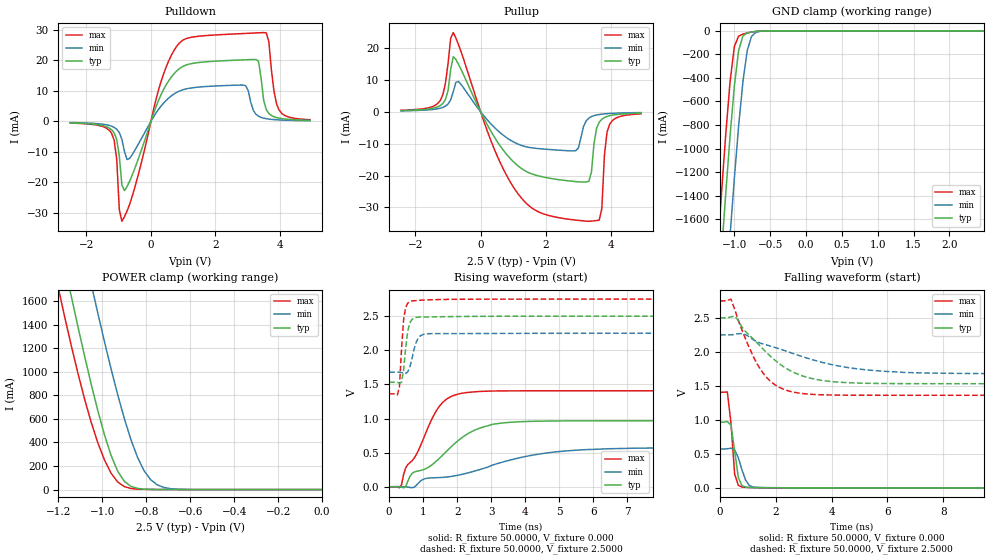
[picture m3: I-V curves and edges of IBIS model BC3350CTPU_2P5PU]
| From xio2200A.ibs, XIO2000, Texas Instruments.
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|   Model BC3350CTPU_2P5PU
[Model]   BC3350CTPU_2P5PU
Model_type   I/O
Polarity   Non-Inverting
Enable   Active-Low
Vinl =   0.7500V
Vinh =   1.7500V
Vmeas =   1.2500V
Cref =  15.0000pF
Rref = 100.0000M
Vref =  0.000V
C_comp   1.5218pF   1.5459pF   1.5123pF
[Temperature Range]   25.0000   0.1250k   -40.0000
[Voltage Range]   2.5000V   2.2500V   2.7500V
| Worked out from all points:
|   slope of the pulldown table from 0 to 0.375 V, typ, clamps not added: 37.2 ohm
|   slope of the pullup table from 0 to 0.375 V, typ, clamps not added: 52.5 ohm
|   GND clamp passes 1 mA (typ) near -0.59 V on its own axis
|   POWER clamp passes 1 mA (typ) near -0.75 V on its own axis
|   rising waveform, R_fixture 50.0000, V_fixture 0.000: 20-80 % time 1.63ns typ, 3.12ns min, 911ps max; typ from 0 V to 0.967 V
|   rising waveform, R_fixture 50.0000, V_fixture 2.5000: 20-80 % time 132ps typ, 185ps min, 110ps max; typ from 1.53 V to 2.5 V
|   falling waveform, R_fixture 50.0000, V_fixture 0.000: 20-80 % time 197ps typ, 276ps min, 166ps max; typ from 0.967 V to 0 V
|   falling waveform, R_fixture 50.0000, V_fixture 2.5000: 20-80 % time 1.61ns typ, 2.84ns min, 994ps max; typ from 2.5 V to 1.53 V
[Pulldown]
| voltage   I(typ)   I(min)   I(max)
-2.5V     -467uA     -355uA     -521uA
-1.22V    -2.719mA   -1.548mA   -3.89mA
-1.06V    -5.93mA    -2.554mA   -12.42mA
-900mV    -20.83mA   -5.841mA   -32.72mA
-660mV    -19.6mA    -12.09mA   -27.16mA
380mV     10.17mA    5.837mA    15.14mA
1.02V     18.17mA    10.47mA    26.8mA
2.94V     20.21mA    11.72mA    28.84mA
3.26V     20.3mA     2.359mA    29mA
3.58V     3.907mA    903.9uA    29.01mA
3.98V     1.074mA    495.1uA    3.709mA
4.94V     373uA      234uA      572uA
[Pullup]
| voltage   I(typ)   I(min)   I(max)
-2.44V    386uA      291uA      479uA
-1.24V    1.945mA    1.132mA    3.544mA
-840mV    17.3mA     6.311mA    24.85mA
-680mV    14.89mA    9.474mA    21.07mA
1.08V     -16.37mA   -9.818mA   -24.74mA
2.92V     -21.89mA   -12.18mA   -33.96mA
3.32V     -21.82mA   -1.989mA   -34.34mA
3.56V     -5.145mA   -999.9uA   -34.1mA
3.72V     -2.328mA   -742.1uA   -30.34mA
3.8V      -1.8mA     -656.3uA   -13.54mA
3.96V     -1.227mA   -532.1uA   -3.918mA
4.92V     -412uA     -247uA     -636uA
[GND_clamp]
| voltage   I(typ)   I(min)   I(max)
-2.5V     -14.57A    -15.39A    -14.11A
-1.24V    -2.437A    -3.32A     -1.92A
-1.18V    -1.901A    -2.781A    -1.388A
-1.12V    -1.385A    -2.254A    -883mA
-1.06V    -898.7mA   -1.743A    -437mA
-1V       -472.1mA   -1.256A    -134.5mA
-940mV    -167.3mA   -809.4mA   -44.68mA
-880mV    -43.65mA   -430.8mA   -28.16mA
-820mV    -17.66mA   -168mA     -18.71mA
-760mV    -9.862mA   -47.59mA   -10.99mA
-700mV    -5.196mA   -13.22mA   -5.204mA
2.48V     104.5pA    201.3nA    85.44pA
[POWER_clamp]
| voltage   I(typ)   I(min)   I(max)
-2.49V    14.56A     15.39A     14.09A
-1.2V     2.157A     3.049A     1.709A
-1.14V    1.631A     2.515A     1.213A
-1.05V    891mA      1.742A     568.1mA
-1.02V    667.6mA    1.494A     395.8mA
-960mV    290.1mA    1.024A     139.6mA
-930mV    156.3mA    806.1mA    65.19mA
-900mV    70.81mA    604.8mA    26.03mA
-840mV    10.16mA    275.4mA    3.647mA
-780mV    1.777mA    84.15mA    1.23mA
-660mV    345.8uA    3.568mA    382.4uA
0V        107.3pA    2.193nA    101.5pA
[Ramp]
| variable   typ   min   max
dV/dt_r   0.5801/1.6072n   0.3429/3.1475n   0.8439/0.8921n
dV/dt_f   0.5811/1.5919n   0.3426/2.8083n   0.8330/0.9837n
R_load = 50.0000
[Rising Waveform]
R_fixture = 50.0000
V_fixture = 0.000
V_fixture_min = 0.000
V_fixture_max = 0.000
| time   V(typ)   V(min)   V(max)
0s        1.141nV    28.31nV    608.5pV
303ps     1.167mV    773.8uV    -16.01mV
484.8ps   1.286mV    -687.1uV   275.1mV
666.7ps   190.5mV    -14.02mV   377.3mV
1.394ns   378.1mV    132.9mV    1.117V
2ns       664.1mV    166.2mV    1.354V
2.667ns   858.8mV    252.3mV    1.396V
3.636ns   946.8mV    401mV      1.405V
5.879ns   966.2mV    545.9mV    1.406V
11.16ns   966.9mV    571.4mV    1.407V
[Rising Waveform]
R_fixture = 50.0000
V_fixture = 2.5000
V_fixture_min = 2.2500
V_fixture_max = 2.7500
| time   V(typ)   V(min)   V(max)
0s        1.532V     1.679V     1.362V
242.4ps   1.53V      1.68V      1.346V
303ps     1.514V     1.679V     1.465V
363.6ps   1.533V     1.673V     2.014V
424.2ps   1.703V     1.664V     2.448V
545.5ps   2.277V     1.684V     2.69V
666.7ps   2.45V      1.868V     2.723V
848.5ps   2.486V     2.174V     2.732V
1.091ns   2.488V     2.24V      2.738V
9.455ns   2.5V       2.25V      2.75V
[Falling Waveform]
R_fixture = 50.0000
V_fixture = 0.000
V_fixture_min = 0.000
V_fixture_max = 0.000
| time   V(typ)   V(min)   V(max)
0s        966.9mV    571.5mV    1.407V
262.6ps   976.8mV    574mV      1.411V
393.9ps   921.3mV    584.2mV    953.5mV
525.3ps   545.8mV    557.5mV    199.6mV
656.6ps   150.4mV    444mV      36.9mV
787.9ps   33.05mV    265.5mV    11.91mV
919.2ps   11.07mV    112.7mV    7.004mV
1.051ns   6.645mV    35.12mV    5.089mV
1.313ns   4.07mV     5.807mV    2.944mV
13ns      403.6nV    1.121uV    308.5nV
[Falling Waveform]
R_fixture = 50.0000
V_fixture = 2.5000
V_fixture_min = 2.2500
V_fixture_max = 2.7500
| time   V(typ)   V(min)   V(max)
0s        2.5V       2.25V      2.75V
393.9ps   2.515V     2.25V      2.776V
525.3ps   2.525V     2.257V     2.628V
1.051ns   2.245V     2.221V     2.059V
1.576ns   2.029V     2.113V     1.671V
1.97ns    1.877V     2.065V     1.516V
2.495ns   1.728V     1.994V     1.421V
3.677ns   1.579V     1.844V     1.368V
5.647ns   1.536V     1.721V     1.362V
13ns      1.532V     1.679V     1.362V
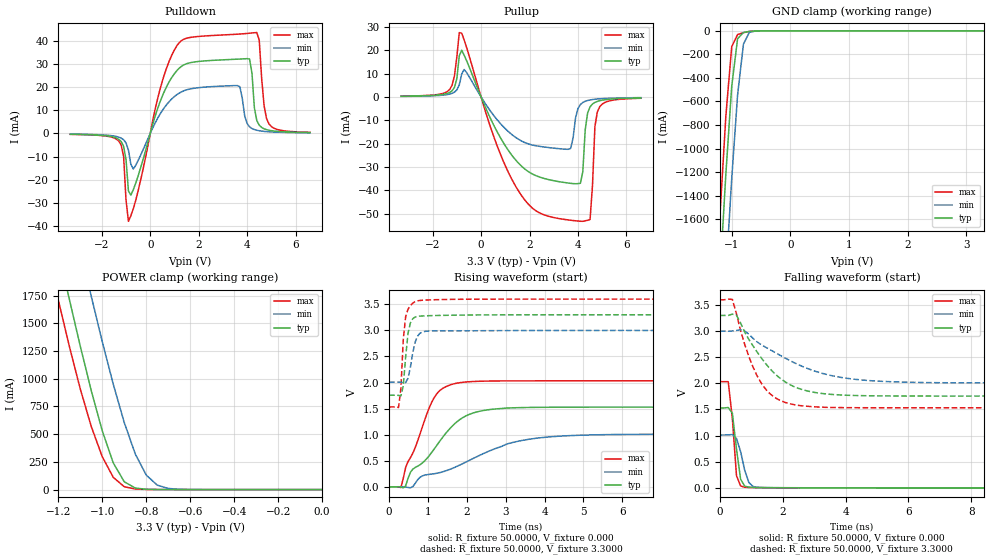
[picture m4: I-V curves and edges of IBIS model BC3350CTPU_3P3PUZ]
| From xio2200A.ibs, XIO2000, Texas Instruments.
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|   Model BC3350CTPU_3P3PUZ
[Model]   BC3350CTPU_3P3PUZ
Model_type   I/O
Polarity   Non-Inverting
Enable   Active-Low
Vinl =   0.9900V
Vinh =   2.3100V
Vmeas =   1.6500V
Cref =  15.0000pF
Rref = 100.0000M
Vref =  0.000V
C_comp   1.9215pF   2.0161pF   1.9194pF
[Temperature Range]   25.0000   0.1250k   -40.0000
[Voltage Range]   3.3000V   3.0000V   3.6000V
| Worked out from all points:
|   slope of the pulldown table from 0 to 0.495 V, typ, clamps not added: 30.8 ohm
|   slope of the pullup table from 0 to 0.495 V, typ, clamps not added: 43 ohm
|   GND clamp passes 1 mA (typ) near -0.59 V on its own axis
|   POWER clamp passes 1 mA (typ) near -0.75 V on its own axis
|   rising waveform, R_fixture 50.0000, V_fixture 0.000: 20-80 % time 1.13ns typ, 2.15ns min, 655ps max; typ from 0 V to 1.53 V
|   rising waveform, R_fixture 50.0000, V_fixture 3.3000: 20-80 % time 123ps typ, 161ps min, 108ps max; typ from 1.76 V to 3.3 V
|   falling waveform, R_fixture 50.0000, V_fixture 0.000: 20-80 % time 191ps typ, 267ps min, 167ps max; typ from 1.53 V to 0 V
|   falling waveform, R_fixture 50.0000, V_fixture 3.3000: 20-80 % time 1.21ns typ, 2.01ns min, 801ps max; typ from 3.3 V to 1.76 V
[Pulldown]
| voltage   I(typ)   I(min)   I(max)
-3.3V     -368uA     -295uA     -396uA
-1.3V     -2.536mA   -1.588mA   -3.308mA
-1.1V     -5.574mA   -2.722mA   -9.851mA
-900mV    -24.93mA   -7.21mA    -38.07mA
-700mV    -24.39mA   -15.39mA   -32.64mA
400mV     13.55mA    8.28mA     19mA
1.1V      27.23mA    16.82mA    38.01mA
3.6V      32.19mA    20.74mA    43.02mA
4.1V      32.24mA    2.869mA    43.43mA
4.4V      5.593mA    1.375mA    43.71mA
4.9V      1.396mA    719.1uA    4.161mA
6.6V      373uA      269uA      490uA
[Pullup]
| voltage   I(typ)   I(min)   I(max)
-3.3V     287uA      231uA      331uA
-1.3V     1.913mA    1.209mA    3.156mA
-800mV    19.97mA    9.765mA    27.29mA
600mV     -13.66mA   -8.958mA   -19.14mA
1.6V      -28.91mA   -18.45mA   -41.12mA
3.7V      -36.98mA   -22mA      -52.77mA
4.2V      -32.06mA   -2.382mA   -53.22mA
4.3V      -14.02mA   -1.866mA   -53mA
4.5V      -4.233mA   -1.292mA   -52.47mA
4.7V      -2.35mA    -983uA     -12.62mA
4.9V      -1.61mA    -791.8uA   -4.169mA
6.6V      -427uA     -295uA     -564uA
[GND_clamp]
| voltage   I(typ)   I(min)   I(max)
-3.3V     -22.46A    -23.25A    -22.02A
-1.3V     -2.984A    -3.868A    -2.468A
-1.2V     -2.078A    -2.96A     -1.563A
-1.1V     -1.218A    -2.081A    -725.2mA
-1V       -472.1mA   -1.256A    -134.5mA
-900mV    -67.36mA   -546.8mA   -32.05mA
-800mV    -14.39mA   -113.3mA   -15.95mA
-700mV    -5.196mA   -13.22mA   -5.204mA
-600mV    -1.073mA   -2.326mA   -726.1uA
-400mV    -6.101uA   -45.85uA   -1.128uA
3.3V      145.6pA    1.139uA    114.6pA
[POWER_clamp]
| voltage   I(typ)   I(min)   I(max)
-3.3V     22.54A     23.35A     22.1A
-1.2V     2.157A     3.049A     1.709A
-1.15V    1.717A     2.603A     1.293A
-1.05V    891mA      1.742A     568.1mA
-1V       529.4mA    1.333A     296.2mA
-950mV    240.5mA    949.8mA    110.5mA
-900mV    70.81mA    604.8mA    26.03mA
-850mV    14.19mA    321.8mA    4.913mA
-800mV    2.945mA    131.1mA    1.574mA
-750mV    995.8uA    40.2mA     925.1uA
-650mV    310.3uA    2.738mA    338.3uA
0V        145.6pA    2.769nA    133.4pA
[Ramp]
| variable   typ   min   max
dV/dt_r   0.9173/1.1031n   0.6069/2.1579n   1.2198/0.6385n
dV/dt_f   0.9259/1.1952n   0.5953/1.9885n   1.2405/0.7929n
R_load = 50.0000
[Rising Waveform]
R_fixture = 50.0000
V_fixture = 0.000
V_fixture_min = 0.000
V_fixture_max = 0.000
| time   V(typ)   V(min)   V(max)
0s        1.596nV    34.76nV    765pV
303ps     -3.798mV   1.436mV    -11.86mV
424.2ps   18.81mV    -3.406mV   372.6mV
606.1ps   337.2mV    958.5uV    641.7mV
1.091ns   656.2mV    244.5mV    1.616V
1.333ns   906.4mV    278.6mV    1.865V
1.636ns   1.175V     357.5mV    1.971V
2.364ns   1.455V     616.4mV    2.026V
4ns       1.526V     949.6mV    2.033V
10.64ns   1.529V     1.011V     2.033V
[Rising Waveform]
R_fixture = 50.0000
V_fixture = 3.3000
V_fixture_min = 3.0000
V_fixture_max = 3.6000
| time   V(typ)   V(min)   V(max)
0s        1.757V     2.008V     1.533V
242.4ps   1.754V     2.01V      1.521V
303ps     1.744V     2.006V     1.897V
363.6ps   1.934V     1.993V     2.827V
424.2ps   2.49V      1.999V     3.262V
484.8ps   2.938V     2.082V     3.404V
545.5ps   3.142V     2.288V     3.477V
727.3ps   3.27V      2.887V     3.566V
1.03ns    3.282V     2.988V     3.585V
8.798ns   3.3V       3V         3.6V
[Falling Waveform]
R_fixture = 50.0000
V_fixture = 0.000
V_fixture_min = 0.000
V_fixture_max = 0.000
| time   V(typ)   V(min)   V(max)
0s        1.529V     1.012V     2.033V
262.6ps   1.538V     1.014V     2.032V
393.9ps   1.431V     1.021V     1.329V
525.3ps   746.4mV    943.9mV    237.1mV
656.6ps   166.4mV    694.6mV    37.02mV
787.9ps   33.26mV    336.2mV    11.23mV
919.2ps   12.01mV    104.2mV    7.887mV
1.051ns   7.815mV    26.71mV    6.015mV
1.313ns   5.068mV    6.785mV    3.557mV
13ns      430.4nV    719.6nV    284.2nV
[Falling Waveform]
R_fixture = 50.0000
V_fixture = 3.3000
V_fixture_min = 3.0000
V_fixture_max = 3.6000
| time   V(typ)   V(min)   V(max)
0s        3.3V       3V         3.6V
393.9ps   3.325V     3.003V     3.607V
525.3ps   3.303V     3.013V     3.33V
919.2ps   2.843V     2.942V     2.515V
1.313ns   2.489V     2.741V     2.006V
1.707ns   2.208V     2.607V     1.746V
2.232ns   1.974V     2.435V     1.609V
3.414ns   1.796V     2.168V     1.541V
4.859ns   1.762V     2.049V     1.533V
13ns      1.757V     2.008V     1.533V
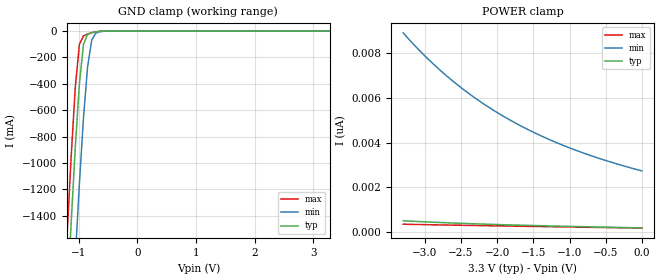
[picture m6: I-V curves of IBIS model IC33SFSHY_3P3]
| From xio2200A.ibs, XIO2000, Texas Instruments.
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|************************ IC33SFSHY @ 3.3V************************
[Model]   IC33SFSHY_3P3
Model_type   Input
Polarity   Non-Inverting
Vinh = 2.31V
Vinl = 0.99V
|   typ   min   max
C_comp   2.050pF   2.121pF   2.045pF
[Model Spec]
|   typ   min   max
Vinh   2.31V   2.10V   2.52V
Vinl   0.99V   0.90V   1.08V
[Temperature Range]   25   125   -40
[Voltage Range]   3.30V   3.00V   3.60V
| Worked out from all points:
|   GND clamp passes 1 mA (typ) near -0.59 V on its own axis
| (Vdd votage range)   1.50V   1.35V   1.65V
[GND_clamp]
| voltage   I(typ)   I(min)   I(max)
-3.3V     -22.44A    -23.23A    -22.01A
-1.2V     -2.062A    -2.938A    -1.55A
-1.13V    -1.453A    -2.319A    -952mA
-1.06V    -884.2mA   -1.722A    -426.9mA
-990mV    -399.1mA   -1.159A    -102.2mA
-920mV    -101.9mA   -657.2mA   -35.63mA
-850mV    -24.63mA   -270.7mA   -22.37mA
-780mV    -11.45mA   -69.98mA   -12.94mA
-710mV    -5.642mA   -15.28mA   -5.841mA
-640mV    -2.142mA   -4.294mA   -1.755mA
3.28V     176.1pA    2.984nA    151.2pA
[POWER_clamp]
| voltage   I(typ)   I(min)   I(max)
-3.3V     501.4pA    8.91nA     345.9pA
-3V       452.8pA    7.88nA     327pA
-2.85V    431pA      7.418nA    318.4pA
-2.65V    404.4pA    6.851nA    306.7pA
-2.3V     362.8pA    5.982nA    287.4pA
-2.1V     341.8pA    5.547nA    277pA
-1.9V     321.8pA    5.152nA    266.4pA
-1.5V     286.5pA    4.465nA    246.1pA
-1.05V    251.1pA    3.828nA    223.6pA
-550mV    216.2pA    3.251nA    198.9pA
0V        178.2pA    2.73nA     169.2pA
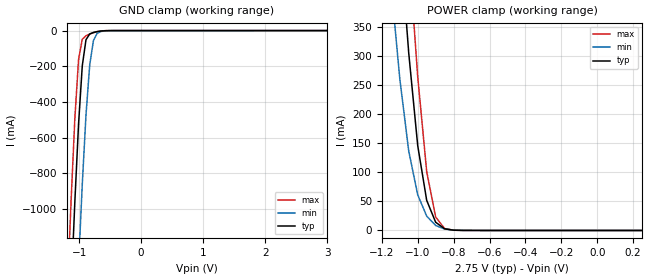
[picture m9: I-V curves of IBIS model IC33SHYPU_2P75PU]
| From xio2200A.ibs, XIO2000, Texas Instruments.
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|   Model IC33SHYPU_2P75PU
[Model]   IC33SHYPU_2P75PU
Model_type   Input
Polarity   Non-Inverting
Vinl =   0.8200V
Vinh =   1.9300V
C_comp   1.6800pF   1.6800pF   1.6800pF
[Temperature Range]   25.0000   0.1250k   -40.0000
[Voltage Range]   2.7500V   2.5000V   3.0000V
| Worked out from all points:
|   GND clamp passes 1 mA (typ) near -0.59 V on its own axis
|   POWER clamp passes 1 mA (typ) near -0.81 V on its own axis
[GND_clamp]
| voltage   I(typ)   I(min)   I(max)
-2.75V    -17.02A    -17.82A    -16.57A
-1.19V    -1.973A    -2.848A    -1.462A
-1.13V    -1.453A    -2.319A    -952.1mA
-1.07V    -961.9mA   -1.806A    -494.2mA
-1.01V    -524.4mA   -1.315A    -162.9mA
-950mV    -197.8mA   -862.4mA   -48.51mA
-890mV    -51.25mA   -472.9mA   -29.05mA
-830mV    -19.02mA   -192.8mA   -19.58mA
-770mV    -10.5mA    -56.14mA   -11.88mA
-710mV    -5.71mA    -15.32mA   -5.951mA
-650mV    -2.581mA   -5.116mA   -2.258mA
3V        0A         12uA       0A
[POWER_clamp]
| voltage   I(typ)   I(min)   I(max)
-2.75V    9.52A      8.73A      10.17A
-1.15V    732.9mA    428mA      979.8mA
-1.1V     506.3mA    260.8mA    722.9mA
-1.05V    304.4mA    136.2mA    480.2mA
-1V       145.7mA    61.22mA    263.9mA
-950mV    51.68mA    24.61mA    101.1mA
-900mV    14.11mA    8.533mA    23.03mA
-850mV    2.875mA    2.487mA    3.233mA
-800mV    506.4uA    691.4uA    386.2uA
-750mV    121.4uA    222.2uA    107.1uA
250mV     0A         500pA      0A
